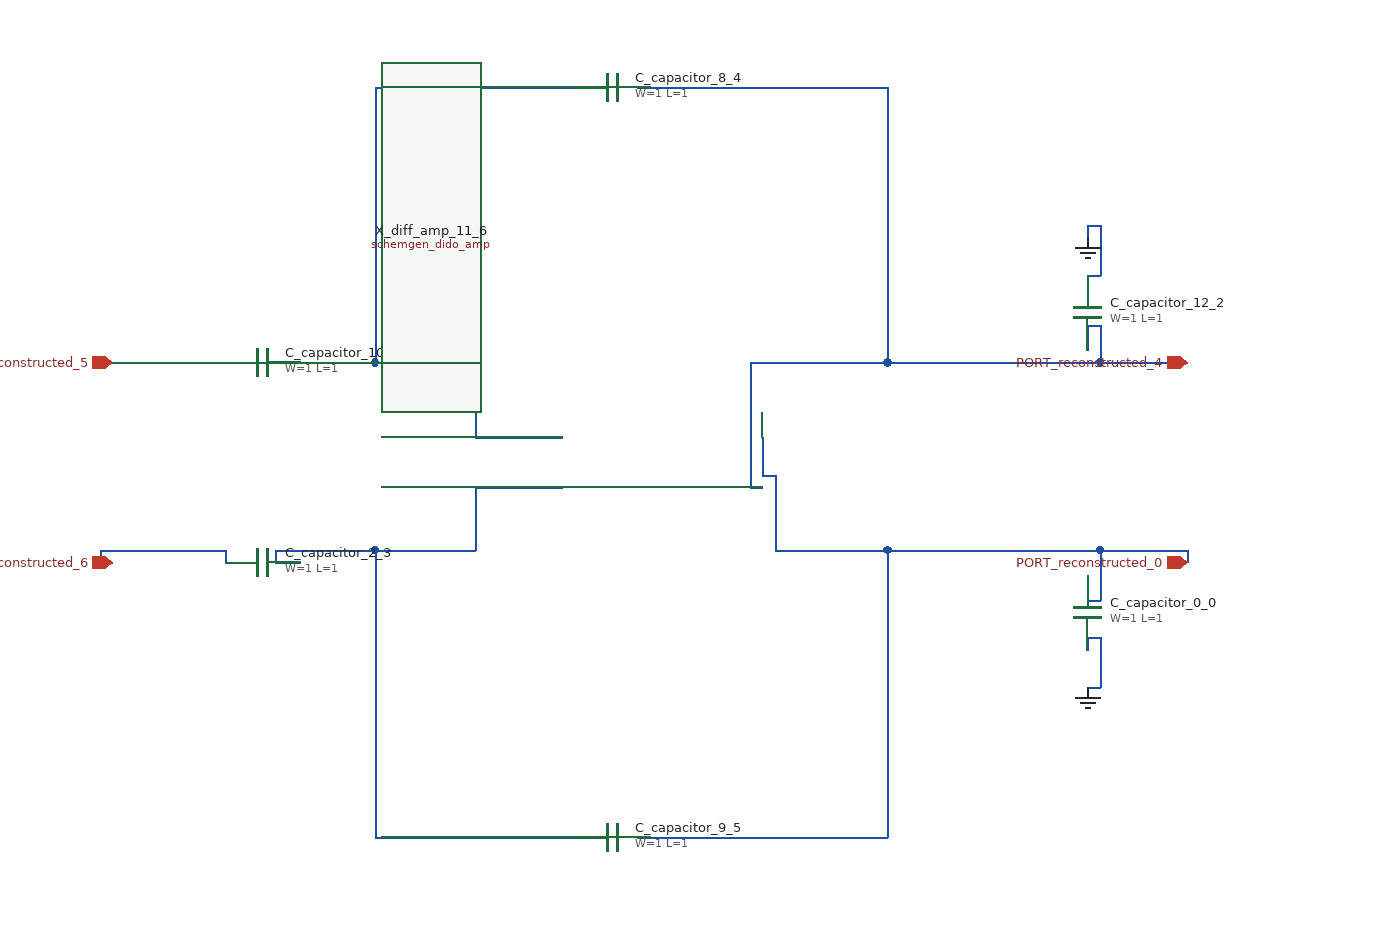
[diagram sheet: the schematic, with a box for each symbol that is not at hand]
v {xschem version=3.4.8 file_version=1.2}
G {}
K {}
V {}
S {}
E {}
C {sky130_fd_pr/cap_mim_m3_1.sym} 940 500 2 0 {name="C_capacitor_0_0" model=cap_mim_m3_1 W=1 L=1 MF=1 spiceprefix=X}
C {sky130_fd_pr/cap_mim_m3_1.sym} 280 300 3 0 {name="C_capacitor_10_1" model=cap_mim_m3_1 W=1 L=1 MF=1 spiceprefix=X}
C {sky130_fd_pr/cap_mim_m3_1.sym} 940 260 0 0 {name="C_capacitor_12_2" model=cap_mim_m3_1 W=1 L=1 MF=1 spiceprefix=X}
C {sky130_fd_pr/cap_mim_m3_1.sym} 280 460 3 0 {name="C_capacitor_2_3" model=cap_mim_m3_1 W=1 L=1 MF=1 spiceprefix=X}
C {sky130_fd_pr/cap_mim_m3_1.sym} 560 80 1 0 {name="C_capacitor_8_4" model=cap_mim_m3_1 W=1 L=1 MF=1 spiceprefix=X}
C {sky130_fd_pr/cap_mim_m3_1.sym} 560 680 1 0 {name="C_capacitor_9_5" model=cap_mim_m3_1 W=1 L=1 MF=1 spiceprefix=X}
C {schemgen_dido_amp.sym} 600 380 2 1 {name="X_diff_amp_11_6"}
C {devices/gnd.sym} 940 560 0 0 {name="l_gnd_1_7" lab="GND"}
C {devices/gnd.sym} 940 200 0 0 {name="l_gnd_5_8" lab="GND"}
C {devices/ipin.sym} 160 300 0 0 {name="p_port_3_9" lab="PORT_reconstructed_5"}
C {devices/ipin.sym} 1020 300 0 0 {name="p_port_4_10" lab="PORT_reconstructed_4"}
C {devices/ipin.sym} 160 460 0 0 {name="p_port_6_11" lab="PORT_reconstructed_6"}
C {devices/ipin.sym} 1020 460 0 0 {name="p_port_7_12" lab="PORT_reconstructed_0"}
N 580 680 590 680 {}
N 590 680 780 680 {}
N 940 490 950 490 {}
N 690 450 780 450 {}
N 780 450 950 450 {}
N 950 450 1020 450 {}
N 680 390 690 390 {}
N 680 390 680 360 {}
N 690 450 690 390 {}
N 780 680 780 450 {}
N 940 490 940 470 {}
N 950 490 950 450 {}
N 1020 460 1020 450 {}
N 940 560 950 560 {}
N 940 520 950 520 {}
N 940 230 950 230 {}
N 940 190 950 190 {}
N 940 530 940 520 {}
N 940 200 940 190 {}
N 950 560 950 520 {}
N 950 230 950 190 {}
N 370 680 530 680 {}
N 530 680 540 680 {}
N 290 460 310 460 {}
N 290 450 370 450 {}
N 370 450 450 450 {}
N 450 400 520 400 {}
N 290 460 290 450 {}
N 370 680 370 450 {}
N 450 450 450 400 {}
N 450 360 520 360 {}
N 290 300 310 300 {}
N 310 300 370 300 {}
N 370 300 450 300 {}
N 370 80 530 80 {}
N 530 80 540 80 {}
N 370 300 370 80 {}
N 450 360 450 300 {}
N 670 400 680 400 {}
N 670 300 780 300 {}
N 780 300 950 300 {}
N 950 300 1020 300 {}
N 940 270 950 270 {}
N 580 80 590 80 {}
N 590 80 780 80 {}
N 670 400 670 300 {}
N 780 300 780 80 {}
N 940 290 940 270 {}
N 950 300 950 270 {}
N 150 300 160 300 {}
N 160 300 250 300 {}
N 150 460 160 460 {}
N 150 450 250 450 {}
N 150 460 150 450 {}
N 250 460 250 450 {}
